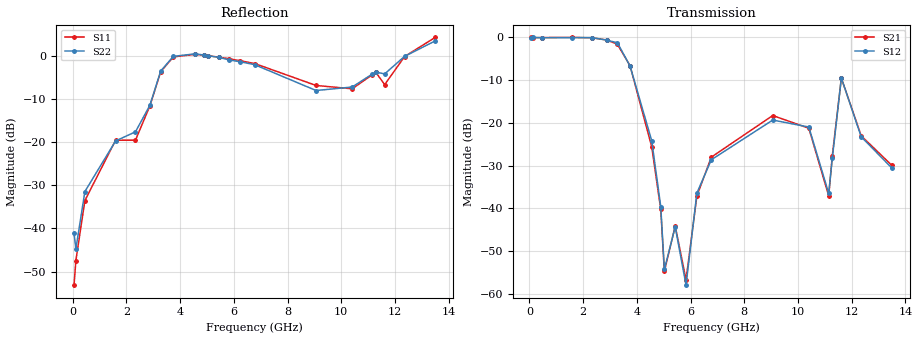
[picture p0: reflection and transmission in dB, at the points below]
! AVX THIN FILM OPERATION
! 0805 Size Low Pass Filter P/N  LP0805A2590AWTR
! Network Analyzer HP8720ES.07.64: Feb 23, 2000 Serial No. US39172382
! Hewlett-Packard
!  2 Feb 2003  04:53:22
! Frequency  S11  S21  S12  S22
# HZ  S  DB R  50
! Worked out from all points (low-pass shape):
!   201 points, 50 MHz to 13.5 GHz, reference 50 ohm
!   highest |S21| = 0.02 dB at 1.597 GHz (marker M1); lowest = -56.7 dB at 5.833 GHz (marker M2)
!   |S21| within 3 dB of the highest: start of sweep to 3.462 GHz
!   lowest |S11| = -53.2 dB at 50 MHz (marker M3), VSWR 1.00, Z = 50.1 - j0.196 ohm
!   |S11| at or under -10 dB: start of sweep to 2.94 GHz
!   |S22| runs from -44.8 to 3.5 dB; largest |S21 - S12| = 0.056
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5e7  -53.15 -63.0  0.01 -1.1  -0.01 -1.5  -41.05 29.6
1.1725e8  -47.49 -90.6  -0.04 -3.1  -0.00 -3.2  -44.81 -126.2
4.535e8  -33.54 -124.3  -0.03 -12.3  -0.05 -12.3  -31.44 -123.7
1.59675e9  -19.55 147.6  0.02 -46.6  -0.04 -46.8  -19.72 150.4
2.3365e9  -19.53 60.1  -0.08 -77.2  -0.03 -77.1  -17.60 47.6
2.8745e9  -11.58 -70.2  -0.58 -108.0  -0.62 -107.0  -11.44 -77.1
3.278e9  -3.65 -133.0  -1.59 -140.3  -1.25 -142.8  -3.48 -131.4
3.74875e9  -0.22 165.3  -6.61 168.9  -6.68 168.3  -0.10 167.8
4.55575e9  0.36 99.2  -25.59 117.1  -24.17 116.9  0.48 97.7
4.892e9  0.19 79.6  -40.24 113.4  -39.57 107.1  0.20 78.0
5.0265e9  0.09 72.3  -54.74 132.2  -54.30 139.4  0.04 70.5
5.43e9  -0.29 51.9  -44.13 -88.4  -44.30 -94.9  -0.31 50.2
5.8335e9  -0.66 33.1  -56.69 26.2  -57.96 9.9  -0.95 31.8
6.237e9  -1.11 15.4  -37.09 66.1  -36.43 65.7  -1.35 14.7
6.775e9  -1.76 -7.0  -28.01 58.0  -28.62 57.1  -2.03 -7.4
9.0615e9  -6.85 -101.1  -18.27 30.5  -19.33 22.3  -8.02 -107.8
1.04065e10  -7.62 167.9  -21.25 -24.5  -20.96 -24.3  -7.21 161.0
1.114625e10  -4.40 128.0  -37.08 -123.2  -36.50 -125.4  -4.24 127.1
1.128075e10  -3.76 120.8  -27.65 158.5  -28.20 153.6  -3.74 120.7
1.1617e10  -6.65 107.1  -9.51 39.1  -9.50 45.0  -4.17 105.4
1.235675e10  -0.15 97.7  -23.03 -35.8  -23.25 -31.7  -0.10 94.1
1.35e10  4.30 79.7  -29.95 -155.6  -30.57 -146.7  3.49 79.9
